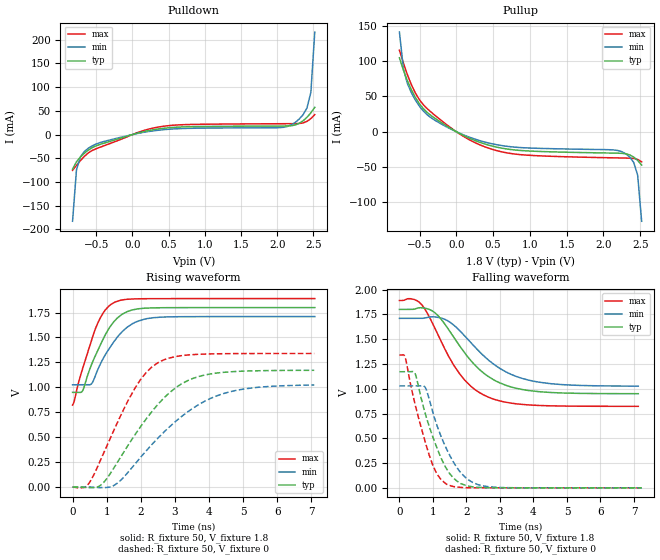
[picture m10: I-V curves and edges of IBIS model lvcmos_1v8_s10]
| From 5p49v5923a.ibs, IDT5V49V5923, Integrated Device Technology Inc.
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[Model]   lvcmos_1v8_s10
Model_type   Output
Polarity   Non-Inverting
|   typ   min   max
C_comp   2pF   1.5pF   2.5pF
Vmeas = 0.9V
Rref = 50
Cref = 0
Vref = 0.9V
|   typ   min   max
[Voltage range]   1.8V   1.71V   1.89V
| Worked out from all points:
|   slope of the pulldown table from 0 to 0.27 V, typ, clamps not added: 27.8 ohm
|   slope of the pullup table from 0 to 0.27 V, typ, clamps not added: 20.5 ohm
|   rising waveform, R_fixture 50, V_fixture 1.8: 20-80 % time 706ps typ, 781ps min, 618ps max; typ from 0.949 V to 1.8 V
|   falling waveform, R_fixture 50, V_fixture 1.8: 20-80 % time 1.27ns typ, 1.39ns min, 1.13ns max; typ from 1.8 V to 0.95 V
|   rising waveform, R_fixture 50, V_fixture 0: 20-80 % time 1.52ns typ, 1.89ns min, 1.16ns max; typ from 0 V to 1.17 V
|   falling waveform, R_fixture 50, V_fixture 0: 20-80 % time 713ps typ, 767ps min, 639ps max; typ from 1.17 V to 0 V
[Pulldown]
|Voltage   I (typ)   I (min)   I (max)
|Note, modeling breaks down at 250mA and above.  This is well beyond the functional   |
|operating range of the device.  Should this scenario occur, catastrophic failure and   |
|possible damage to the device and/or board is of higher concern than the I-V curve   |
|behavior.  The IBIS checker will flag currents in excess of 10A with warnings.  Lines   |
|with currents in excess of 0.35 A have been commented out.  The points still remain|
|available to the user if the user desires to use them.   |
|-1.80000e+00   -1.57092e+02   -1.41660e+02   -1.83995e+02
|-1.74600e+00   -1.46319e+02   -1.32498e+02   -1.70563e+02
|-1.69200e+00   -1.35562e+02   -1.23354e+02   -1.57144e+02
|-1.63800e+00   -1.24824e+02   -1.14233e+02   -1.43740e+02
|-1.58400e+00   -1.14109e+02   -1.05138e+02   -1.30355e+02
|-1.53000e+00   -1.03423e+02   -9.60753e+01   -1.16994e+02
|-1.47600e+00   -9.27746e+01   -8.70544e+01   -1.03664e+02
|-1.42200e+00   -8.21756e+01   -7.80869e+01   -9.03763e+01
|-1.36800e+00   -7.16432e+01   -6.91893e+01   -7.71482e+01
|-1.31400e+00   -6.12071e+01   -6.03887e+01   -6.40088e+01
|-1.26000e+00   -5.09082e+01   -5.17162e+01   -5.10143e+01
|-1.20600e+00   -4.07943e+01   -4.32058e+01   -3.82282e+01
|-1.15200e+00   -3.09098e+01   -3.48894e+01   -2.57313e+01
|-1.09800e+00   -2.12573e+01   -2.67671e+01   -1.35244e+01
|-1.04400e+00   -1.17728e+01   -1.88010e+01   -2.45353e+00
|-9.90000e-01   -2.91831e+00   -1.09337e+01   -2.97019e-01
|-9.36000e-01   -4.77009e-01   -3.38966e+00   -1.12027e-01
|-8.82000e-01   -1.29374e-01   -7.06978e-01   -8.68143e-02
-828mV    -72.84mA   -182.7mA   -75.44mA
-774mV    -57.29mA   -74.54mA   -65.18mA
-720mV    -47.53mA   -46.96mA   -54.96mA
-612mV    -32.88mA   -28.97mA   -38.85mA
-504mV    -23.85mA   -19.98mA   -29.92mA
144mV     5.844mA    4.468mA    8.03mA
468mV     13.85mA    10.82mA    18.28mA
2.034V    18.01mA    14.65mA    22.86mA
2.25V     20.27mA    25.62mA    23.05mA
2.412V    36.39mA    55.95mA    27.84mA
2.466V    45.85mA    88.7mA     33.66mA
2.52V     57.39mA    216.1mA    41.98mA
| 2.57400e+00   7.10857e-02   8.66354e-01   5.27949e-02
| 2.62800e+00   9.37369e-02   4.39442e+00   6.57495e-02
| 2.68200e+00   1.97051e-01   1.54844e+01   7.88307e-02
| 2.73600e+00   9.30483e-01   2.77711e+01   9.02161e-02
| 2.79000e+00   6.43287e+00   4.00711e+01   1.05367e-01
| 2.84400e+00   2.08648e+01   5.23910e+01   1.78908e-01
| 2.89800e+00   3.56342e+01   6.47347e+01   1.04359e+00
| 2.95200e+00   5.04292e+01   7.71014e+01   1.09790e+01
| 3.00600e+00   6.52553e+01   8.94875e+01   2.98573e+01
| 3.06000e+00   8.01095e+01   1.01888e+02   4.87713e+01
| 3.11400e+00   9.49852e+01   1.14301e+02   6.77282e+01
| 3.16800e+00   1.09877e+02   1.26722e+02   8.67195e+01
| 3.22200e+00   1.24780e+02   1.39150e+02   1.05734e+02
| 3.27600e+00   1.39691e+02   1.51583e+02   1.24764e+02
| 3.33000e+00   1.54609e+02   1.64020e+02   1.43805e+02
| 3.38400e+00   1.69532e+02   1.76461e+02   1.62853e+02
| 3.43800e+00   1.84458e+02   1.88905e+02   1.81907e+02
| 3.49200e+00   1.99388e+02   2.01352e+02   2.00965e+02
| 3.54600e+00   2.14321e+02   2.13801e+02   2.20026e+02
| 3.60000e+00   2.29256e+02   2.26251e+02   2.39090e+02
[Pullup]
|Voltage   I (typ)   I (min)   I (max)
|Note, modeling breaks down at 250mA and above.  This is well beyond the functional   |
|operating range of the device.  Should this scenario occur, catastrophic failure and   |
|possible damage to the device and/or board is of higher concern than the I-V curve   |
|behavior.  The IBIS checker will flag currents in excess of 10A with warnings.  Lines   |
|with currents in excess of 0.35 A have been commented out.  The points still remain|
|available to the user if the user desires to use them.   |
|-1.80000e+00   2.29324e+02   2.05561e+02   2.70950e+02
|-1.74600e+00   2.14388e+02   1.93112e+02   2.51881e+02
|-1.69200e+00   1.99454e+02   1.80666e+02   2.32814e+02
|-1.63800e+00   1.84523e+02   1.68223e+02   2.13749e+02
|-1.58400e+00   1.69595e+02   1.55783e+02   1.94687e+02
|-1.53000e+00   1.54671e+02   1.43347e+02   1.75629e+02
|-1.47600e+00   1.39752e+02   1.30916e+02   1.56575e+02
|-1.42200e+00   1.24839e+02   1.18492e+02   1.37528e+02
|-1.36800e+00   1.09935e+02   1.06075e+02   1.18489e+02
|-1.31400e+00   9.50414e+01   9.36681e+01   9.94610e+01
|-1.26000e+00   8.01638e+01   8.12751e+01   8.04510e+01
|-1.20600e+00   6.53077e+01   6.88998e+01   6.14679e+01
|-1.15200e+00   5.04800e+01   5.65464e+01   4.25228e+01
|-1.09800e+00   3.56830e+01   4.42171e+01   2.36201e+01
|-1.04400e+00   2.09115e+01   3.19094e+01   5.44052e+00
|-9.90000e-01   6.47738e+00   1.96171e+01   5.58000e-01
|-9.36000e-01   9.72696e-01   7.44537e+00   1.86913e-01
|-8.82000e-01   2.36778e-01   1.50232e+00   1.46983e-01
|-8.28000e-01   1.30667e-01   3.59994e-01   1.31178e-01
-774mV    104.6mA    141.1mA    115.3mA
-720mV    87.19mA    88.95mA    97.38mA
-666mV    72.2mA     68.44mA    80.78mA
-558mV    48.63mA    44.92mA    54.95mA
-396mV    27.21mA    23.95mA    32.63mA
90mV      -4.938mA   -4.143mA   -6.144mA
576mV     -22.36mA   -18.87mA   -27.44mA
1.008V    -27.38mA   -23.11mA   -33.44mA
2.25V     -30.58mA   -28.23mA   -37.15mA
2.412V    -35.89mA   -43.49mA   -37.83mA
2.466V    -40.65mA   -61.5mA    -39.22mA
2.52V     -47.11mA   -126.7mA   -42.57mA
| 2.57400e+00   -5.55826e-02   -4.32696e-01   -4.82493e-02
| 2.62800e+00   -7.01515e-02   -1.98518e+00   -5.60882e-02
| 2.68200e+00   -1.25769e-01   -8.32163e+00   -6.52773e-02
| 2.73600e+00   -4.72524e-01   -1.61672e+01   -7.47005e-02
| 2.79000e+00   -2.91321e+00   -2.40936e+01   -8.69040e-02
| 2.84400e+00   -1.17674e+01   -3.21570e+01   -1.29831e-01
| 2.89800e+00   -2.12518e+01   -4.04076e+01   -5.40444e-01
| 2.95200e+00   -3.09043e+01   -4.88544e+01   -5.48325e+00
| 3.00600e+00   -4.07886e+01   -5.74767e+01   -1.75589e+01
| 3.06000e+00   -5.09033e+01   -6.62376e+01   -2.98541e+01
| 3.11400e+00   -6.12001e+01   -7.51066e+01   -4.24547e+01
| 3.16800e+00   -7.16365e+01   -8.40528e+01   -5.53200e+01
| 3.22200e+00   -8.21688e+01   -9.30572e+01   -6.83693e+01
| 3.27600e+00   -9.27678e+01   -1.02107e+02   -8.15423e+01
| 3.33000e+00   -1.03416e+02   -1.11191e+02   -9.47928e+01
| 3.38400e+00   -1.14102e+02   -1.20305e+02   -1.08096e+02
| 3.43800e+00   -1.24816e+02   -1.29441e+02   -1.21437e+02
| 3.49200e+00   -1.35555e+02   -1.38597e+02   -1.34807e+02
| 3.54600e+00   -1.46312e+02   -1.47769e+02   -1.48199e+02
| 3.60000e+00   -1.57084e+02   -1.56955e+02   -1.61609e+02
[Ramp]
|   typ   min   max
dV/dt_r   0.707/1.529n   0.618/1.901n   0.808/1.168n
dV/dt_f   0.52/1.282n  0.419/1.402n   0.652/1.145n
R_load =   50
[Rising Waveform]
R_fixture = 50
V_fixture = 1.8   |Vcc_typ
V_fixture_min = 1.71 |Vcc_min
V_fixture_max = 1.89 |Vcc_max
C_fixture = 0.0p
| Time   typ   min   max
| 0.00000e+00   9.49472e-01   1.02539e+00   8.22230e-01
| 2.47507e-12   9.49472e-01   1.02539e+00   8.22230e-01
| 4.34525e-12   9.49472e-01   1.02539e+00   8.22230e-01
| 4.57959e-12   9.49472e-01   1.02539e+00   8.22230e-01
| 7.76228e-12   9.49472e-01   1.02539e+00   8.22230e-01
| 1.40250e-11   9.49472e-01   1.02539e+00   8.22230e-01
| 1.46859e-11   9.49472e-01   1.02539e+00   8.22230e-01
| 2.75535e-11   9.49472e-01   1.02539e+00   8.22230e-01
| 3.89155e-11   9.49472e-01   1.02539e+00   8.22230e-01
| 4.27651e-11   9.49472e-01   1.02539e+00   8.22230e-01
| 5.19470e-11   9.49472e-01   1.02539e+00   8.22230e-01
| 6.09735e-11   9.49472e-01   1.02539e+00   8.22230e-01
| 6.28654e-11   9.49472e-01   1.02539e+00   8.22230e-01
| 7.18356e-11   9.49472e-01   1.02539e+00   8.22230e-01
| 7.20853e-11   9.49472e-01   1.02539e+00   8.22230e-01
| 7.57553e-11   9.49472e-01   1.02539e+00   8.22230e-01
| 7.80681e-11   9.49472e-01   1.02539e+00   8.22230e-01
| 7.93945e-11   9.49472e-01   1.02539e+00   8.22230e-01
| 8.55419e-11   9.49472e-01   1.02539e+00   8.22230e-01
| 9.55053e-11   9.49472e-01   1.02539e+00   8.22230e-01
| 9.79251e-11   9.49472e-01   1.02539e+00   8.22230e-01
| 1.07935e-10   9.49472e-01   1.02539e+00   8.22230e-01
| 1.13391e-10   9.49472e-01   1.02539e+00   8.22230e-01
| 1.17787e-10   9.49472e-01   1.02539e+00   8.22230e-01
| 1.27332e-10   9.49472e-01   1.02539e+00   8.22230e-01
| 1.31896e-10   9.49472e-01   1.02539e+00   8.22230e-01
| 1.39384e-10   9.49472e-01   1.02539e+00   8.22230e-01
| 1.47496e-10   9.49472e-01   1.02539e+00   8.22230e-01
| 1.52113e-10   9.49472e-01   1.02539e+00   8.22230e-01
| 1.61711e-10   9.49472e-01   1.02539e+00   8.22229e-01
| 1.73234e-10   9.49472e-01   1.02539e+00   8.22229e-01
| 1.77396e-10   9.49472e-01   1.02539e+00   8.22229e-01
| 1.88921e-10   9.49472e-01   1.02539e+00   8.22229e-01
| 1.98884e-10   9.49472e-01   1.02539e+00   8.22230e-01
| 2.05039e-10   9.49472e-01   1.02539e+00   8.22230e-01
| 2.10800e-10   9.49472e-01   1.02539e+00   8.22230e-01
| 2.20271e-10   9.49472e-01   1.02539e+00   8.22230e-01
| 2.25890e-10   9.49472e-01   1.02539e+00   8.22230e-01
| 2.33125e-10   9.49472e-01   1.02539e+00   8.22230e-01
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0s        949.5mV    1.025V     822.2mV
51.94ps   949.5mV    1.025V     864.2mV
299.1ps   968.3mV    1.025V     1.192V
549.7ps   1.223V     1.033V     1.468V
719.3ps   1.355V     1.161V     1.629V
955.6ps   1.524V     1.323V     1.774V
1.258ns   1.675V     1.479V     1.857V
1.753ns   1.777V     1.637V     1.886V
2.367ns   1.797V     1.698V     1.889V
7.106ns   1.8V       1.71V      1.89V
[Falling Waveform]
R_fixture = 50
V_fixture = 1.8   |Vcc_typ
V_fixture_min = 1.71 |Vcc_min
V_fixture_max = 1.89 |Vcc_max
C_fixture = 0.0p
| Time   typ   min   max
| 0.00000e+00   1.80000e+00   1.71000e+00   1.89000e+00
| 2.47507e-12   1.80000e+00   1.71000e+00   1.89000e+00
| 4.34525e-12   1.80000e+00   1.71000e+00   1.89000e+00
| 4.57959e-12   1.80000e+00   1.71000e+00   1.89000e+00
| 7.76228e-12   1.80000e+00   1.71000e+00   1.89000e+00
| 1.40250e-11   1.80000e+00   1.71000e+00   1.89000e+00
| 1.46859e-11   1.80000e+00   1.71000e+00   1.89000e+00
| 2.75535e-11   1.80000e+00   1.71000e+00   1.89000e+00
| 3.89154e-11   1.80000e+00   1.71000e+00   1.89000e+00
| 4.27652e-11   1.80000e+00   1.71000e+00   1.89000e+00
| 5.19470e-11   1.80000e+00   1.71000e+00   1.89000e+00
| 6.09735e-11   1.80000e+00   1.71000e+00   1.89000e+00
| 6.28654e-11   1.80000e+00   1.71000e+00   1.89000e+00
| 7.18356e-11   1.80000e+00   1.71000e+00   1.89000e+00
| 7.20853e-11   1.80000e+00   1.71000e+00   1.89000e+00
| 7.57554e-11   1.80000e+00   1.71000e+00   1.89000e+00
| 7.80681e-11   1.80000e+00   1.71000e+00   1.89000e+00
| 7.93945e-11   1.80000e+00   1.71000e+00   1.89000e+00
| 8.55420e-11   1.80000e+00   1.71000e+00   1.89000e+00
| 9.55081e-11   1.80000e+00   1.71000e+00   1.89000e+00
| 9.79276e-11   1.80000e+00   1.71000e+00   1.89000e+00
| 1.07935e-10   1.80000e+00   1.71000e+00   1.89000e+00
| 1.13392e-10   1.80000e+00   1.71000e+00   1.89000e+00
| 1.17787e-10   1.80000e+00   1.71000e+00   1.89000e+00
| 1.27334e-10   1.80000e+00   1.71000e+00   1.89000e+00
| 1.31895e-10   1.80000e+00   1.71000e+00   1.89000e+00
| 1.39383e-10   1.80000e+00   1.71000e+00   1.89000e+00
| 1.47496e-10   1.80000e+00   1.71000e+00   1.89000e+00
| 1.52111e-10   1.80000e+00   1.71000e+00   1.89000e+00
| 1.61708e-10   1.80000e+00   1.71000e+00   1.89000e+00
| 1.73952e-10   1.80000e+00   1.71000e+00   1.89000e+00
| 1.78551e-10   1.80000e+00   1.71000e+00   1.89000e+00
| 1.90103e-10   1.80000e+00   1.71000e+00   1.89000e+00
| 1.99713e-10   1.80000e+00   1.71000e+00   1.89000e+00
| 2.06408e-10   1.80000e+00   1.71000e+00   1.89000e+00
| 2.11341e-10   1.80000e+00   1.71000e+00   1.89000e+00
| 2.21498e-10   1.80000e+00   1.71000e+00   1.89000e+00
| 2.28608e-10   1.80000e+00   1.71000e+00   1.89000e+00
| 2.34502e-10   1.80000e+00   1.71000e+00   1.89000e+00
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0s        1.8V       1.71V      1.89V
575.4ps   1.816V     1.71V      1.877V
1.032ns   1.773V     1.725V     1.629V
1.412ns   1.625V     1.691V     1.363V
1.811ns   1.425V     1.582V     1.144V
2.2ns     1.257V     1.44V      1.006V
2.661ns   1.122V     1.288V     914.3mV
3.34ns    1.017V     1.144V     854.3mV
4.139ns   971.2mV    1.068V     831.3mV
7.129ns   949.8mV    1.026V     822.3mV
[Rising Waveform]
R_fixture = 50
V_fixture = 0
C_fixture = 0.0p
| Time   typ   min   max
| 0.00000e+00   1.64764e-09   5.29878e-08   7.41092e-10
| 2.47507e-12   1.64808e-09   5.29882e-08   7.41588e-10
| 4.34525e-12   1.64844e-09   5.29885e-08   7.41965e-10
| 4.57959e-12   1.64848e-09   5.29885e-08   7.42012e-10
| 7.76228e-12   1.64907e-09   5.29890e-08   7.42565e-10
| 1.40250e-11   1.64960e-09   5.29898e-08   7.42702e-10
| 1.46859e-11   1.64959e-09   5.29898e-08   7.42713e-10
| 2.75535e-11   1.64824e-09   5.29894e-08   7.40446e-10
| 3.89155e-11   1.64598e-09   5.29875e-08   7.38885e-10
| 4.27651e-11   1.64520e-09   5.29869e-08   7.38451e-10
| 5.19470e-11   1.64334e-09   5.29842e-08   7.37319e-10
| 6.09735e-11   1.63922e-09   5.29802e-08   7.33604e-10
| 6.28654e-11   1.63758e-09   5.29791e-08   7.32644e-10
| 7.18356e-11   1.62894e-09   5.29682e-08   7.25644e-10
| 7.20853e-11   1.62861e-09   5.29677e-08   7.25395e-10
| 7.57553e-11   1.62315e-09   5.29598e-08   7.21852e-10
| 7.80681e-11   1.62045e-09   5.29543e-08   7.21773e-10
| 7.93945e-11   1.61893e-09   5.29528e-08   7.23566e-10
| 8.55419e-11   1.63232e-09   5.29579e-08   7.53332e-10
| 9.55053e-11   1.75281e-09   5.30250e-08   9.10320e-10
| 9.79251e-11   1.78417e-09   5.30663e-08   9.63331e-10
| 1.07935e-10   2.01554e-09   5.32579e-08   1.16237e-09
| 1.13391e-10   2.12070e-09   5.33825e-08   1.22856e-09
| 1.17787e-10   2.19284e-09   5.34829e-08   1.17411e-09
| 1.27332e-10   2.16836e-09   5.35798e-08   9.41080e-10
| 1.31896e-10   1.99649e-09   5.34822e-08   7.60239e-10
| 1.39384e-10   1.63760e-09   5.33093e-08   2.76126e-10
| 1.47496e-10   9.54664e-10   5.26651e-08   -5.64806e-10
| 1.52113e-10   2.29160e-10   5.21078e-08   -1.08324e-09
| 1.61711e-10   -1.33223e-09   5.05305e-08   -2.59378e-09
| 1.73234e-10   -3.40328e-09   4.81841e-08   -3.73375e-09
| 1.77396e-10   -3.64159e-09   4.74507e-08   -4.03505e-09
| 1.88921e-10   -3.94715e-09   4.63189e-08   -2.94582e-09
| 1.98884e-10   -2.96753e-09   4.64931e-08   -8.13419e-10
| 2.05039e-10   -1.86702e-09   4.68353e-08   9.62052e-10
| 2.10800e-10   -7.46113e-10   4.76074e-08   2.62405e-09
| 2.20271e-10   1.39951e-09   4.88766e-08   5.58346e-09
| 2.25890e-10   2.93778e-09   4.98950e-08   7.28294e-09
| 2.33125e-10   5.24192e-09   5.13058e-08   8.97170e-09
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0s        1.648nV    52.99nV    741.1pV
445.2ps   -7.592mV   116.9uV    21.09mV
891.3ps   37.94mV    -6.365mV   323.7mV
1.307ns   243.3mV    36.28mV    640.2mV
1.82ns    518.4mV    225.9mV    984.9mV
2.16ns    683mV      362.7mV    1.148V
2.5ns     827.4mV    488.6mV    1.246V
3.335ns   1.06V      743.1mV    1.323V
4.396ns   1.149V     934mV      1.337V
7.09ns    1.171V     1.023V     1.339V
[Falling Waveform]
R_fixture = 50
V_fixture = 0
C_fixture = 0.0p
| Time   typ   min   max
| 0.00000e+00   1.17132e+00   1.02789e+00   1.33940e+00
| 1.13526e-09   1.17132e+00   1.02789e+00   1.33940e+00
| 1.18935e-09   1.17132e+00   1.02789e+00   1.33938e+00
| 1.21301e-09   1.17132e+00   1.02789e+00   1.33936e+00
| 1.22889e-09   1.17132e+00   1.02789e+00   1.33933e+00
| 1.25482e-09   1.17132e+00   1.02789e+00   1.33928e+00
| 1.28510e-09   1.17132e+00   1.02789e+00   1.33930e+00
| 1.30215e-09   1.17132e+00   1.02789e+00   1.33943e+00
| 1.32150e-09   1.17132e+00   1.02789e+00   1.33973e+00
| 1.33178e-09   1.17132e+00   1.02789e+00   1.33997e+00
| 1.34262e-09   1.17132e+00   1.02789e+00   1.34035e+00
| 1.35401e-09   1.17132e+00   1.02789e+00   1.34093e+00
| 1.37263e-09   1.17131e+00   1.02789e+00   1.34179e+00
| 1.38272e-09   1.17131e+00   1.02789e+00   1.34181e+00
| 1.39622e-09   1.17131e+00   1.02789e+00   1.34071e+00
| 1.40774e-09   1.17130e+00   1.02789e+00   1.33843e+00
| 1.41694e-09   1.17130e+00   1.02789e+00   1.33521e+00
| 1.42732e-09   1.17129e+00   1.02789e+00   1.32976e+00
| 1.43719e-09   1.17128e+00   1.02789e+00   1.32245e+00
| 1.45223e-09   1.17127e+00   1.02789e+00   1.30671e+00
| 1.46352e-09   1.17126e+00   1.02789e+00   1.29129e+00
| 1.47425e-09   1.17125e+00   1.02789e+00   1.27400e+00
| 1.48889e-09   1.17122e+00   1.02789e+00   1.24828e+00
| 1.50273e-09   1.17120e+00   1.02789e+00   1.22300e+00
| 1.50889e-09   1.17119e+00   1.02789e+00   1.21155e+00
| 1.52580e-09   1.17118e+00   1.02789e+00   1.17944e+00
| 1.54477e-09   1.17120e+00   1.02790e+00   1.14386e+00
| 1.54573e-09   1.17120e+00   1.02790e+00   1.14212e+00
| 1.55869e-09   1.17126e+00   1.02789e+00   1.11870e+00
| 1.57995e-09   1.17146e+00   1.02789e+00   1.08217e+00
| 1.58368e-09   1.17151e+00   1.02789e+00   1.07576e+00
| 1.60135e-09   1.17183e+00   1.02789e+00   1.04678e+00
| 1.60360e-09   1.17187e+00   1.02789e+00   1.04320e+00
| 1.61846e-09   1.17231e+00   1.02789e+00   1.01949e+00
| 1.63020e-09   1.17277e+00   1.02789e+00   1.00119e+00
| 1.64204e-09   1.17328e+00   1.02788e+00   9.82867e-01
| 1.65478e-09   1.17370e+00   1.02788e+00   9.63489e-01
| 1.66934e-09   1.17371e+00   1.02787e+00   9.41692e-01
| 1.67985e-09   1.17319e+00   1.02786e+00   9.26090e-01
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0s        1.171V     1.028V     1.339V
181ps     1.171V     1.028V     1.307V
448.3ps   1.164V     1.028V     869.2mV
762.3ps   759.2mV    1.016V     471.9mV
1.11ns    411.3mV    639.6mV    145.6mV
1.413ns   188.9mV    388mV      35.28mV
1.618ns   97.13mV    255.6mV    12.78mV
1.923ns   31.38mV    120.6mV    2.396mV
2.513ns   2.605mV    18.42mV    156.5uV
7.229ns   -719.5nV   -325.7nV   -433.4nV
